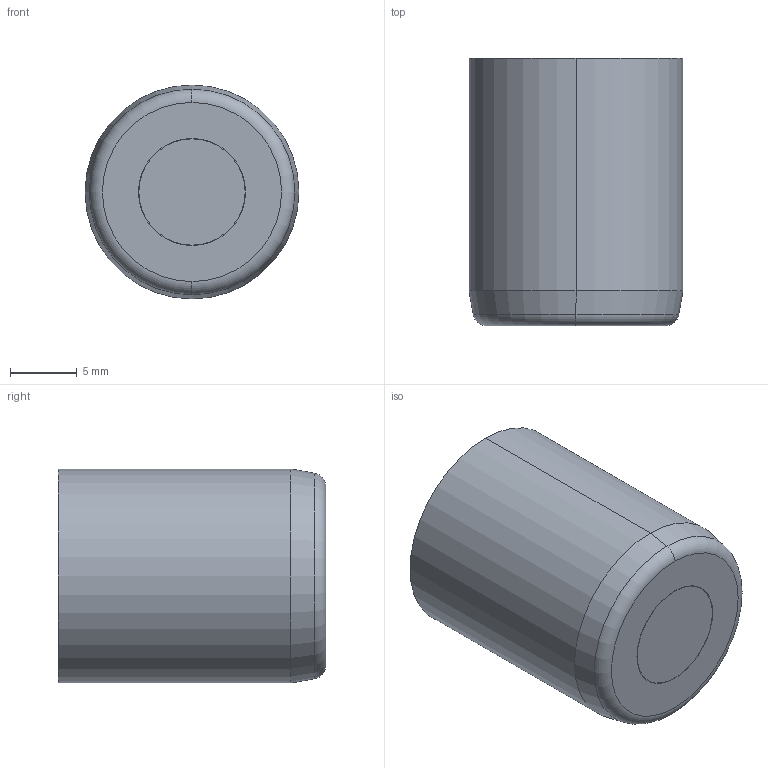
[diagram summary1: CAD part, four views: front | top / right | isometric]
STEP (ISO 10303-21) file: header records copied from the file, then geometry measured from it (millimetres).
FILE_DESCRIPTION (( 'STEP AP214' ), '1' );
FILE_NAME ('FA 168708-20.STEP', '2013-10-01T10:08:22', ( '' ), ( '' ), 'SwSTEP 2.0', 'SolidWorks 2011', '' );
FILE_SCHEMA (( 'AUTOMOTIVE_DESIGN' ));
Length unit declared in the file: millimetre
Products named in the file (6): FA 168708-20-1; IA 8717SF; FA 168700-2 comprimido; FA 168708-20; FA 168700-1; FA 168700-3
Assembly tree (5 placements, depth 2):
  FA 168708-20
    FA 168700-2 comprimido
    FA 168700-3
    FA 168700-1
    IA 8717SF
    FA 168708-20-1
Bounding box: 16 x 20 x 16 mm (x, y, z)
Volume: 3762.4 mm3; surface area: 2713.4 mm2
Topology: 5 solids, 5 shells, 398 faces, 1033 edges, 675 vertices
Faces by surface type: cylinder 193, plane 159, cone 34, torus 10, bspline 2
Entity records: 13831 total; most frequent: CARTESIAN_POINT 3438, DIRECTION 2247, ORIENTED_EDGE 2062, EDGE_CURVE 1031, AXIS2_PLACEMENT_3D 844, VERTEX_POINT 675, LINE 559, VECTOR 559
One B-rep face of a CAD part: STEP entity #10901.
In plain terms, the cylindrical face has radius 8 mm (diameter 16 mm), a partial arc.
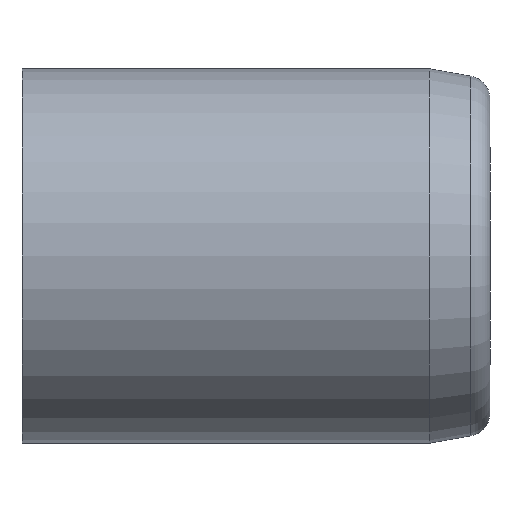
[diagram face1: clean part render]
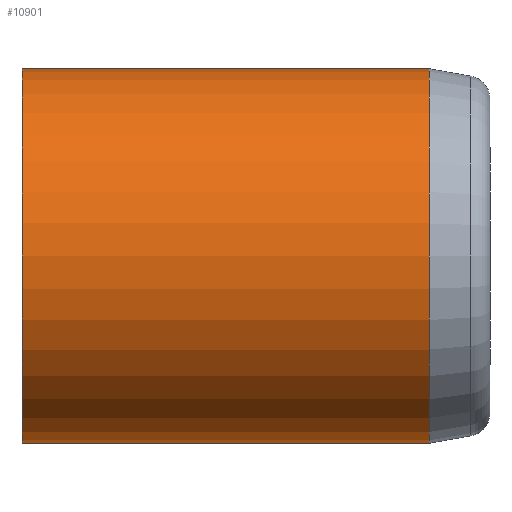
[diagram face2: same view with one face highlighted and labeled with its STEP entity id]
Its self-contained STEP definition (entity closure, numbers rounded to 3 decimals):
#2196 = EDGE_LOOP ( 'NONE', ( #6339, #6359, #6327, #6300 ) ) ;
#2795 = VERTEX_POINT ( 'NONE', #12674 ) ;
#2829 = VERTEX_POINT ( 'NONE', #12739 ) ;
#2833 = VERTEX_POINT ( 'NONE', #12704 ) ;
#2838 = VERTEX_POINT ( 'NONE', #12734 ) ;
#6300 = ORIENTED_EDGE ( 'NONE', *, *, #11200, .F. ) ;
#6327 = ORIENTED_EDGE ( 'NONE', *, *, #11205, .T. ) ;
#6339 = ORIENTED_EDGE ( 'NONE', *, *, #11241, .F. ) ;
#6359 = ORIENTED_EDGE ( 'NONE', *, *, #11314, .F. ) ;
#7416 = DIRECTION ( 'NONE',  ( 0., 1., 0. ) ) ;
#7444 = LINE ( 'NONE', #7445, #9970 ) ;
#7445 = CARTESIAN_POINT ( 'NONE',  ( 0., -9.87, -8. ) ) ;
#7801 = CARTESIAN_POINT ( 'NONE',  ( 0., -9.87, 8. ) ) ;
#7818 = DIRECTION ( 'NONE',  ( 0., 1., 0. ) ) ;
#7830 = CARTESIAN_POINT ( 'NONE',  ( 0., 20.13, 0. ) ) ;
#7836 = DIRECTION ( 'NONE',  ( 0., 0., 1. ) ) ;
#7839 = LINE ( 'NONE', #7801, #9917 ) ;
#7841 = DIRECTION ( 'NONE',  ( 0., 1., 0. ) ) ;
#8752 = DIRECTION ( 'NONE',  ( 0., 0., 1. ) ) ;
#8767 = CARTESIAN_POINT ( 'NONE',  ( 0., -9.87, 0. ) ) ;
#8771 = FACE_OUTER_BOUND ( 'NONE', #2196, .T. ) ;
#8772 = DIRECTION ( 'NONE',  ( 0., 1., 0. ) ) ;
#8775 = CYLINDRICAL_SURFACE ( 'NONE', #10169, 8. ) ;
#9262 = CARTESIAN_POINT ( 'NONE',  ( 0., 2.73, 0. ) ) ;
#9298 = DIRECTION ( 'NONE',  ( 0., 0., -1. ) ) ;
#9322 = DIRECTION ( 'NONE',  ( 0., -1., 0. ) ) ;
#9894 = CIRCLE ( 'NONE', #9937, 8. ) ;
#9917 = VECTOR ( 'NONE', #7841, 1000. ) ;
#9937 = AXIS2_PLACEMENT_3D ( 'NONE', #7830, #7818, #7836 ) ;
#9970 = VECTOR ( 'NONE', #7416, 1000. ) ;
#10007 = CIRCLE ( 'NONE', #10008, 8. ) ;
#10008 = AXIS2_PLACEMENT_3D ( 'NONE', #9262, #9322, #9298 ) ;
#10169 = AXIS2_PLACEMENT_3D ( 'NONE', #8767, #8772, #8752 ) ;
#10901 = ADVANCED_FACE ( 'NONE', ( #8771 ), #8775, .T. ) ;
#11200 = EDGE_CURVE ( 'NONE', #2838, #2829, #9894, .T. ) ;
#11205 = EDGE_CURVE ( 'NONE', #2833, #2829, #7839, .T. ) ;
#11241 = EDGE_CURVE ( 'NONE', #2795, #2838, #7444, .T. ) ;
#11314 = EDGE_CURVE ( 'NONE', #2833, #2795, #10007, .T. ) ;
#12674 = CARTESIAN_POINT ( 'NONE',  ( 0., 2.73, -8. ) ) ;
#12704 = CARTESIAN_POINT ( 'NONE',  ( 0., 2.73, 8. ) ) ;
#12734 = CARTESIAN_POINT ( 'NONE',  ( 0., 20.13, -8. ) ) ;
#12739 = CARTESIAN_POINT ( 'NONE',  ( 0., 20.13, 8. ) ) ;
